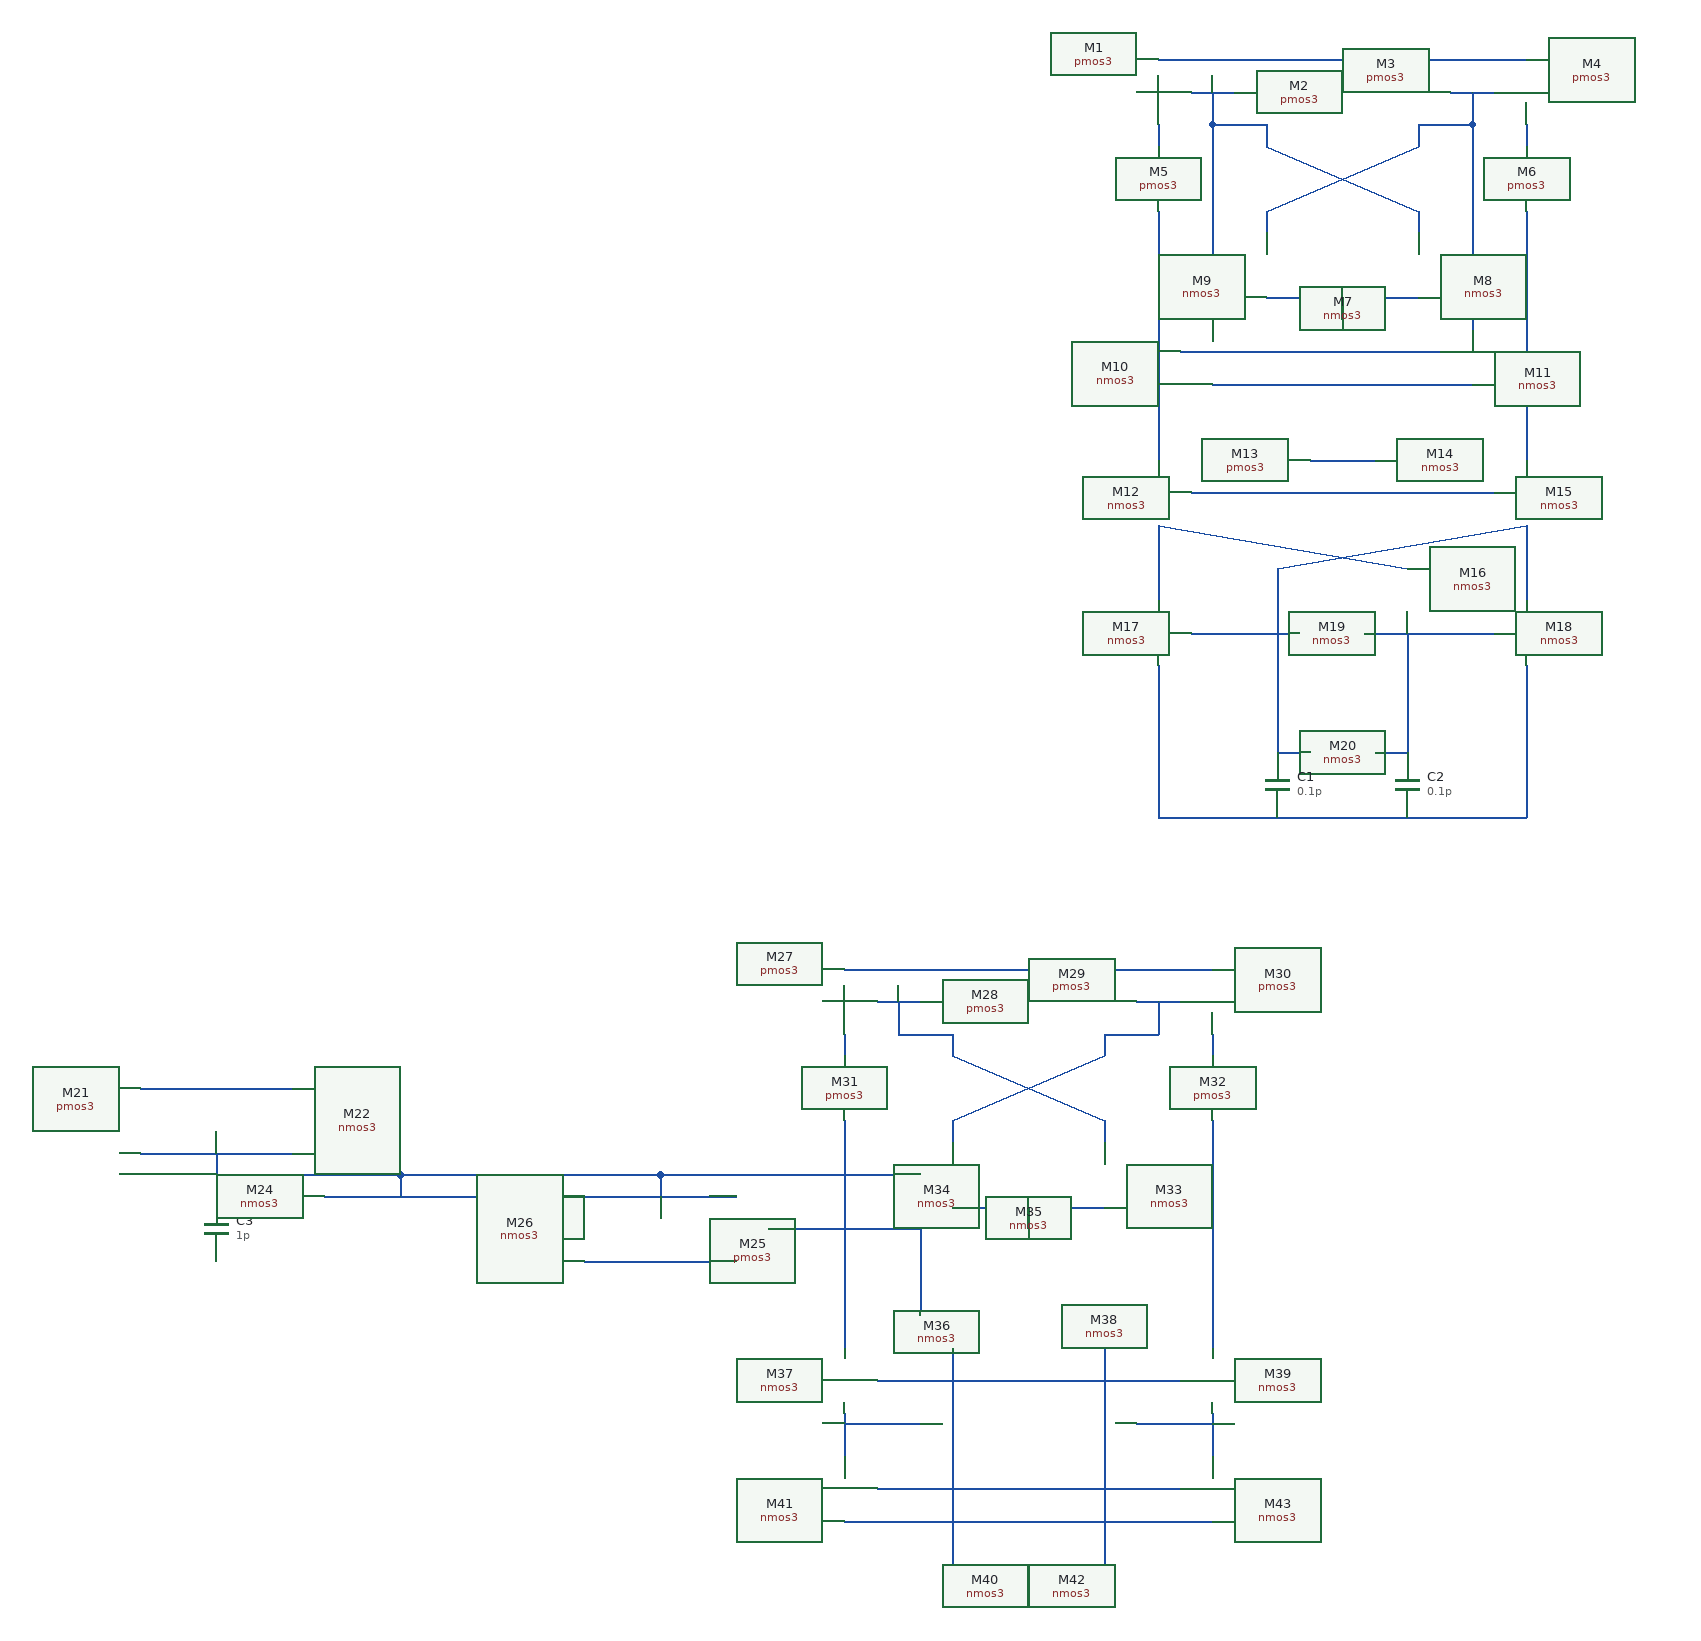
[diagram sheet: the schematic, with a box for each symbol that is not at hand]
v {xschem version=3.4.3 file_version=1.2
}
G {}
K {}
V {}
S {}
E {}
N -260 -400 80 -400 {
lab=#net1}
N -230 -370 -190 -370 {
lab=#net2}
N -210 -370 -210 -340 {
lab=#net2}
N -210 -340 -160 -340 {
lab=#net2}
N 10 -370 50 -370 {
lab=#net3}
N 30 -370 30 -340 {
lab=#net3}
N -20 -340 30 -340 {
lab=#net3}
N -160 -340 -160 -320 {
lab=#net2}
N -20 -260 -20 -240 {
lab=#net2}
N -20 -340 -20 -320 {
lab=#net3}
N -160 -260 -160 -240 {
lab=#net3}
N -160 -260 -20 -320 {
lab=#net3}
N -160 -320 -20 -260 {
lab=#net2}
N 80 -340 80 -320 {
lab=#net4}
N -260 -340 -260 -320 {
lab=#net5}
N -160 -180 -20 -180 {
lab=#net6}
N -90 -180 -90 -160 {
lab=#net6}
N -240 -130 0 -130 {
lab=#net7}
N -210 -100 30 -100 {
lab=#net8}
N -210 -340 -210 -160 {
lab=#net2}
N 30 -340 30 -150 {
lab=#net3}
N -260 -260 -260 -30 {
lab=#net9}
N -120 -30 -60 -30 {
lab=#net10}
N 80 -260 80 -30 {
lab=#net11}
N -230 -0 50 0 {
lab=#net12}
N -230 130 -130 130 {
lab=#net13}
N -70 130 50 130 {
lab=#net14}
N -260 30 -260 100 {
lab=#net15}
N 80 30 80 100 {
lab=#net13}
N -260 30 -30 70 {
lab=#net15}
N -150 70 80 30 {
lab=#net13}
N -150 70 -150 130 {
lab=#net13}
N -150 130 -150 240 {
lab=#net13}
N -150 240 -120 240 {
lab=#net13}
N -60 240 -30 240 {
lab=#net14}
N -30 130 -30 240 {
lab=#net14}
N -260 160 -260 300 {
lab=#net16}
N -260 300 80 300 {
lab=#net16}
N 80 160 80 300 {
lab=#net16}
N -1200 610 -1060 610 {
lab=#net17}
N -1200 550 -1060 550 {
lab=#net18}
N -1130 610 -1130 650 {
lab=#net17}
N -1130 630 -960 630 {
lab=#net17}
N -1030 650 -890 650 {
lab=#net17}
N -960 630 -960 650 {
lab=#net17}
N -790 650 -650 650 {
lab=#net17}
N -960 630 -720 630 {
lab=#net17}
N -720 630 -720 650 {
lab=#net17}
N -790 710 -650 710 {
lab=#net19}
N -550 440 -210 440 {
lab=#net20}
N -520 470 -480 470 {
lab=#net21}
N -500 470 -500 500 {
lab=#net21}
N -500 500 -450 500 {
lab=#net21}
N -280 470 -240 470 {
lab=#net22}
N -260 470 -260 500 {
lab=#net22}
N -310 500 -260 500 {
lab=#net22}
N -450 500 -450 520 {
lab=#net21}
N -310 580 -310 600 {
lab=#net21}
N -310 500 -310 520 {
lab=#net22}
N -450 580 -450 600 {
lab=#net22}
N -450 580 -310 520 {
lab=#net22}
N -450 520 -310 580 {
lab=#net21}
N -210 500 -210 520 {
lab=#net23}
N -550 500 -550 520 {
lab=#net24}
N -450 660 -310 660 {
lab=#net25}
N -380 660 -380 680 {
lab=#net25}
N -720 630 -480 630 {
lab=#net17}
N -550 580 -550 790 {
lab=#net26}
N -620 680 -480 680 {
lab=#net27}
N -480 680 -480 760 {
lab=#net27}
N -210 580 -210 790 {
lab=#net28}
N -520 820 -240 820 {
lab=#net29}
N -550 850 -550 890 {
lab=#net30}
N -550 860 -480 860 {
lab=#net30}
N -210 850 -210 890 {
lab=#net30}
N -280 860 -210 860 {
lab=#net30}
N -310 790 -310 990 {}
N -450 790 -450 990 {}
N -550 950 -210 950 {}
N -520 920 -240 920 {}
C {madvlsi/pmos3.sym} -260 -370 0 1 {name=M1
L=0.15
W=1
body=VDD
nf=1
mult=1
ad="'int((nf+1)/2) * W/nf * 0.29'" 
pd="'2*int((nf+1)/2) * (W/nf + 0.29)'"
as="'int((nf+2)/2) * W/nf * 0.29'" 
ps="'2*int((nf+2)/2) * (W/nf + 0.29)'"
nrd="'0.29 / W'" nrs="'0.29 / W'"
sa=0 sb=0 sd=0
model=pfet_01v8
spiceprefix=X
}
C {madvlsi/pmos3.sym} -160 -370 0 0 {name=M2
L=0.15
W=1
body=VDD
nf=1
mult=1
ad="'int((nf+1)/2) * W/nf * 0.29'" 
pd="'2*int((nf+1)/2) * (W/nf + 0.29)'"
as="'int((nf+2)/2) * W/nf * 0.29'" 
ps="'2*int((nf+2)/2) * (W/nf + 0.29)'"
nrd="'0.29 / W'" nrs="'0.29 / W'"
sa=0 sb=0 sd=0
model=pfet_01v8
spiceprefix=X
}
C {madvlsi/pmos3.sym} -20 -370 0 1 {name=M3
L=0.15
W=1
body=VDD
nf=1
mult=1
ad="'int((nf+1)/2) * W/nf * 0.29'" 
pd="'2*int((nf+1)/2) * (W/nf + 0.29)'"
as="'int((nf+2)/2) * W/nf * 0.29'" 
ps="'2*int((nf+2)/2) * (W/nf + 0.29)'"
nrd="'0.29 / W'" nrs="'0.29 / W'"
sa=0 sb=0 sd=0
model=pfet_01v8
spiceprefix=X
}
C {madvlsi/pmos3.sym} 80 -370 0 0 {name=M4
L=0.15
W=1
body=VDD
nf=1
mult=1
ad="'int((nf+1)/2) * W/nf * 0.29'" 
pd="'2*int((nf+1)/2) * (W/nf + 0.29)'"
as="'int((nf+2)/2) * W/nf * 0.29'" 
ps="'2*int((nf+2)/2) * (W/nf + 0.29)'"
nrd="'0.29 / W'" nrs="'0.29 / W'"
sa=0 sb=0 sd=0
model=pfet_01v8
spiceprefix=X
}
C {madvlsi/pmos3.sym} -260 -290 0 0 {name=M5
L=0.15
W=1
body=VDD
nf=1
mult=1
ad="'int((nf+1)/2) * W/nf * 0.29'" 
pd="'2*int((nf+1)/2) * (W/nf + 0.29)'"
as="'int((nf+2)/2) * W/nf * 0.29'" 
ps="'2*int((nf+2)/2) * (W/nf + 0.29)'"
nrd="'0.29 / W'" nrs="'0.29 / W'"
sa=0 sb=0 sd=0
model=pfet_01v8
spiceprefix=X
}
C {madvlsi/pmos3.sym} 80 -290 0 1 {name=M6
L=0.15
W=1
body=VDD
nf=1
mult=1
ad="'int((nf+1)/2) * W/nf * 0.29'" 
pd="'2*int((nf+1)/2) * (W/nf + 0.29)'"
as="'int((nf+2)/2) * W/nf * 0.29'" 
ps="'2*int((nf+2)/2) * (W/nf + 0.29)'"
nrd="'0.29 / W'" nrs="'0.29 / W'"
sa=0 sb=0 sd=0
model=pfet_01v8
spiceprefix=X
}
C {madvlsi/nmos3.sym} -90 -130 0 0 {name=M7
L=0.15
W=1
body=GND
nf=1
mult=1
ad="'int((nf+1)/2) * W/nf * 0.29'" 
pd="'2*int((nf+1)/2) * (W/nf + 0.29)'"
as="'int((nf+2)/2) * W/nf * 0.29'" 
ps="'2*int((nf+2)/2) * (W/nf + 0.29)'"
nrd="'0.29 / W'" nrs="'0.29 / W'"
sa=0 sb=0 sd=0
model=nfet_01v8
spiceprefix=X
}
C {madvlsi/nmos3.sym} -20 -210 0 1 {name=M8
L=0.15
W=1
body=GND
nf=1
mult=1
ad="'int((nf+1)/2) * W/nf * 0.29'" 
pd="'2*int((nf+1)/2) * (W/nf + 0.29)'"
as="'int((nf+2)/2) * W/nf * 0.29'" 
ps="'2*int((nf+2)/2) * (W/nf + 0.29)'"
nrd="'0.29 / W'" nrs="'0.29 / W'"
sa=0 sb=0 sd=0
model=nfet_01v8
spiceprefix=X
}
C {madvlsi/nmos3.sym} -160 -210 0 0 {name=M9
L=0.15
W=1
body=GND
nf=1
mult=1
ad="'int((nf+1)/2) * W/nf * 0.29'" 
pd="'2*int((nf+1)/2) * (W/nf + 0.29)'"
as="'int((nf+2)/2) * W/nf * 0.29'" 
ps="'2*int((nf+2)/2) * (W/nf + 0.29)'"
nrd="'0.29 / W'" nrs="'0.29 / W'"
sa=0 sb=0 sd=0
model=nfet_01v8
spiceprefix=X
}
C {madvlsi/nmos3.sym} -210 -130 0 0 {name=M10
L=0.15
W=1
body=GND
nf=1
mult=1
ad="'int((nf+1)/2) * W/nf * 0.29'" 
pd="'2*int((nf+1)/2) * (W/nf + 0.29)'"
as="'int((nf+2)/2) * W/nf * 0.29'" 
ps="'2*int((nf+2)/2) * (W/nf + 0.29)'"
nrd="'0.29 / W'" nrs="'0.29 / W'"
sa=0 sb=0 sd=0
model=nfet_01v8
spiceprefix=X
}
C {madvlsi/nmos3.sym} 30 -130 0 0 {name=M11
L=0.15
W=1
body=GND
nf=1
mult=1
ad="'int((nf+1)/2) * W/nf * 0.29'" 
pd="'2*int((nf+1)/2) * (W/nf + 0.29)'"
as="'int((nf+2)/2) * W/nf * 0.29'" 
ps="'2*int((nf+2)/2) * (W/nf + 0.29)'"
nrd="'0.29 / W'" nrs="'0.29 / W'"
sa=0 sb=0 sd=0
model=nfet_01v8
spiceprefix=X
}
C {madvlsi/nmos3.sym} -260 0 0 1 {name=M12
L=0.15
W=1
body=GND
nf=1
mult=1
ad="'int((nf+1)/2) * W/nf * 0.29'" 
pd="'2*int((nf+1)/2) * (W/nf + 0.29)'"
as="'int((nf+2)/2) * W/nf * 0.29'" 
ps="'2*int((nf+2)/2) * (W/nf + 0.29)'"
nrd="'0.29 / W'" nrs="'0.29 / W'"
sa=0 sb=0 sd=0
model=nfet_01v8
spiceprefix=X
}
C {madvlsi/pmos3.sym} -150 -30 0 1 {name=M13
L=0.15
W=1
body=VDD
nf=1
mult=1
ad="'int((nf+1)/2) * W/nf * 0.29'" 
pd="'2*int((nf+1)/2) * (W/nf + 0.29)'"
as="'int((nf+2)/2) * W/nf * 0.29'" 
ps="'2*int((nf+2)/2) * (W/nf + 0.29)'"
nrd="'0.29 / W'" nrs="'0.29 / W'"
sa=0 sb=0 sd=0
model=pfet_01v8
spiceprefix=X
}
C {madvlsi/nmos3.sym} -30 -30 0 0 {name=M14
L=0.15
W=1
body=GND
nf=1
mult=1
ad="'int((nf+1)/2) * W/nf * 0.29'" 
pd="'2*int((nf+1)/2) * (W/nf + 0.29)'"
as="'int((nf+2)/2) * W/nf * 0.29'" 
ps="'2*int((nf+2)/2) * (W/nf + 0.29)'"
nrd="'0.29 / W'" nrs="'0.29 / W'"
sa=0 sb=0 sd=0
model=nfet_01v8
spiceprefix=X
}
C {madvlsi/nmos3.sym} 80 0 0 0 {name=M15
L=0.15
W=1
body=GND
nf=1
mult=1
ad="'int((nf+1)/2) * W/nf * 0.29'" 
pd="'2*int((nf+1)/2) * (W/nf + 0.29)'"
as="'int((nf+2)/2) * W/nf * 0.29'" 
ps="'2*int((nf+2)/2) * (W/nf + 0.29)'"
nrd="'0.29 / W'" nrs="'0.29 / W'"
sa=0 sb=0 sd=0
model=nfet_01v8
spiceprefix=X
}
C {madvlsi/nmos3.sym} -30 100 0 0 {name=M16
L=0.15
W=1
body=GND
nf=1
mult=1
ad="'int((nf+1)/2) * W/nf * 0.29'" 
pd="'2*int((nf+1)/2) * (W/nf + 0.29)'"
as="'int((nf+2)/2) * W/nf * 0.29'" 
ps="'2*int((nf+2)/2) * (W/nf + 0.29)'"
nrd="'0.29 / W'" nrs="'0.29 / W'"
sa=0 sb=0 sd=0
model=nfet_01v8
spiceprefix=X
}
C {madvlsi/nmos3.sym} -260 130 0 1 {name=M17
L=0.15
W=1
body=GND
nf=1
mult=1
ad="'int((nf+1)/2) * W/nf * 0.29'" 
pd="'2*int((nf+1)/2) * (W/nf + 0.29)'"
as="'int((nf+2)/2) * W/nf * 0.29'" 
ps="'2*int((nf+2)/2) * (W/nf + 0.29)'"
nrd="'0.29 / W'" nrs="'0.29 / W'"
sa=0 sb=0 sd=0
model=nfet_01v8
spiceprefix=X
}
C {madvlsi/nmos3.sym} 80 130 0 0 {name=M18
L=0.15
W=1
body=GND
nf=1
mult=1
ad="'int((nf+1)/2) * W/nf * 0.29'" 
pd="'2*int((nf+1)/2) * (W/nf + 0.29)'"
as="'int((nf+2)/2) * W/nf * 0.29'" 
ps="'2*int((nf+2)/2) * (W/nf + 0.29)'"
nrd="'0.29 / W'" nrs="'0.29 / W'"
sa=0 sb=0 sd=0
model=nfet_01v8
spiceprefix=X
}
C {madvlsi/nmos3.sym} -100 130 3 0 {name=M19
L=0.15
W=1
body=GND
nf=1
mult=1
ad="'int((nf+1)/2) * W/nf * 0.29'" 
pd="'2*int((nf+1)/2) * (W/nf + 0.29)'"
as="'int((nf+2)/2) * W/nf * 0.29'" 
ps="'2*int((nf+2)/2) * (W/nf + 0.29)'"
nrd="'0.29 / W'" nrs="'0.29 / W'"
sa=0 sb=0 sd=0
model=nfet_01v8
spiceprefix=X
}
C {madvlsi/nmos3.sym} -90 240 3 0 {name=M20
L=0.15
W=1
body=GND
nf=1
mult=1
ad="'int((nf+1)/2) * W/nf * 0.29'" 
pd="'2*int((nf+1)/2) * (W/nf + 0.29)'"
as="'int((nf+2)/2) * W/nf * 0.29'" 
ps="'2*int((nf+2)/2) * (W/nf + 0.29)'"
nrd="'0.29 / W'" nrs="'0.29 / W'"
sa=0 sb=0 sd=0
model=nfet_01v8
spiceprefix=X
}
C {madvlsi/capacitor.sym} -150 270 0 0 {name=C1
value=0.1p
m=1}
C {madvlsi/capacitor.sym} -30 270 0 0 {name=C2
value=0.1p
m=1}
C {madvlsi/pmos3.sym} -1200 580 0 0 {name=M21
L=0.15
W=1
body=VDD
nf=1
mult=1
ad="'int((nf+1)/2) * W/nf * 0.29'" 
pd="'2*int((nf+1)/2) * (W/nf + 0.29)'"
as="'int((nf+2)/2) * W/nf * 0.29'" 
ps="'2*int((nf+2)/2) * (W/nf + 0.29)'"
nrd="'0.29 / W'" nrs="'0.29 / W'"
sa=0 sb=0 sd=0
model=pfet_01v8
spiceprefix=X
}
C {madvlsi/nmos3.sym} -1060 580 2 0 {name=M22
L=0.15
W=1
body=GND
nf=1
mult=1
ad="'int((nf+1)/2) * W/nf * 0.29'" 
pd="'2*int((nf+1)/2) * (W/nf + 0.29)'"
as="'int((nf+2)/2) * W/nf * 0.29'" 
ps="'2*int((nf+2)/2) * (W/nf + 0.29)'"
nrd="'0.29 / W'" nrs="'0.29 / W'"
sa=0 sb=0 sd=0
model=nfet_01v8
spiceprefix=X
}
C {madvlsi/capacitor.sym} -1130 680 0 0 {name=C3
value=1p
m=1}
C {madvlsi/pmos3.sym} -890 680 0 1 {name=M23
L=0.15
W=1
body=VDD
nf=1
mult=1
ad="'int((nf+1)/2) * W/nf * 0.29'" 
pd="'2*int((nf+1)/2) * (W/nf + 0.29)'"
as="'int((nf+2)/2) * W/nf * 0.29'" 
ps="'2*int((nf+2)/2) * (W/nf + 0.29)'"
nrd="'0.29 / W'" nrs="'0.29 / W'"
sa=0 sb=0 sd=0
model=pfet_01v8
spiceprefix=X
}
C {madvlsi/nmos3.sym} -1030 680 2 1 {name=M24
L=0.15
W=1
body=GND
nf=1
mult=1
ad="'int((nf+1)/2) * W/nf * 0.29'" 
pd="'2*int((nf+1)/2) * (W/nf + 0.29)'"
as="'int((nf+2)/2) * W/nf * 0.29'" 
ps="'2*int((nf+2)/2) * (W/nf + 0.29)'"
nrd="'0.29 / W'" nrs="'0.29 / W'"
sa=0 sb=0 sd=0
model=nfet_01v8
spiceprefix=X
}
C {madvlsi/pmos3.sym} -650 680 0 1 {name=M25
L=0.15
W=1
body=VDD
nf=1
mult=1
ad="'int((nf+1)/2) * W/nf * 0.29'" 
pd="'2*int((nf+1)/2) * (W/nf + 0.29)'"
as="'int((nf+2)/2) * W/nf * 0.29'" 
ps="'2*int((nf+2)/2) * (W/nf + 0.29)'"
nrd="'0.29 / W'" nrs="'0.29 / W'"
sa=0 sb=0 sd=0
model=pfet_01v8
spiceprefix=X
}
C {madvlsi/nmos3.sym} -790 680 2 1 {name=M26
L=0.15
W=1
body=GND
nf=1
mult=1
ad="'int((nf+1)/2) * W/nf * 0.29'" 
pd="'2*int((nf+1)/2) * (W/nf + 0.29)'"
as="'int((nf+2)/2) * W/nf * 0.29'" 
ps="'2*int((nf+2)/2) * (W/nf + 0.29)'"
nrd="'0.29 / W'" nrs="'0.29 / W'"
sa=0 sb=0 sd=0
model=nfet_01v8
spiceprefix=X
}
C {madvlsi/pmos3.sym} -550 470 0 1 {name=M27
L=0.15
W=1
body=VDD
nf=1
mult=1
ad="'int((nf+1)/2) * W/nf * 0.29'" 
pd="'2*int((nf+1)/2) * (W/nf + 0.29)'"
as="'int((nf+2)/2) * W/nf * 0.29'" 
ps="'2*int((nf+2)/2) * (W/nf + 0.29)'"
nrd="'0.29 / W'" nrs="'0.29 / W'"
sa=0 sb=0 sd=0
model=pfet_01v8
spiceprefix=X
}
C {madvlsi/pmos3.sym} -450 470 0 0 {name=M28
L=0.15
W=1
body=VDD
nf=1
mult=1
ad="'int((nf+1)/2) * W/nf * 0.29'" 
pd="'2*int((nf+1)/2) * (W/nf + 0.29)'"
as="'int((nf+2)/2) * W/nf * 0.29'" 
ps="'2*int((nf+2)/2) * (W/nf + 0.29)'"
nrd="'0.29 / W'" nrs="'0.29 / W'"
sa=0 sb=0 sd=0
model=pfet_01v8
spiceprefix=X
}
C {madvlsi/pmos3.sym} -310 470 0 1 {name=M29
L=0.15
W=1
body=VDD
nf=1
mult=1
ad="'int((nf+1)/2) * W/nf * 0.29'" 
pd="'2*int((nf+1)/2) * (W/nf + 0.29)'"
as="'int((nf+2)/2) * W/nf * 0.29'" 
ps="'2*int((nf+2)/2) * (W/nf + 0.29)'"
nrd="'0.29 / W'" nrs="'0.29 / W'"
sa=0 sb=0 sd=0
model=pfet_01v8
spiceprefix=X
}
C {madvlsi/pmos3.sym} -210 470 0 0 {name=M30
L=0.15
W=1
body=VDD
nf=1
mult=1
ad="'int((nf+1)/2) * W/nf * 0.29'" 
pd="'2*int((nf+1)/2) * (W/nf + 0.29)'"
as="'int((nf+2)/2) * W/nf * 0.29'" 
ps="'2*int((nf+2)/2) * (W/nf + 0.29)'"
nrd="'0.29 / W'" nrs="'0.29 / W'"
sa=0 sb=0 sd=0
model=pfet_01v8
spiceprefix=X
}
C {madvlsi/pmos3.sym} -550 550 0 0 {name=M31
L=0.15
W=1
body=VDD
nf=1
mult=1
ad="'int((nf+1)/2) * W/nf * 0.29'" 
pd="'2*int((nf+1)/2) * (W/nf + 0.29)'"
as="'int((nf+2)/2) * W/nf * 0.29'" 
ps="'2*int((nf+2)/2) * (W/nf + 0.29)'"
nrd="'0.29 / W'" nrs="'0.29 / W'"
sa=0 sb=0 sd=0
model=pfet_01v8
spiceprefix=X
}
C {madvlsi/pmos3.sym} -210 550 0 1 {name=M32
L=0.15
W=1
body=VDD
nf=1
mult=1
ad="'int((nf+1)/2) * W/nf * 0.29'" 
pd="'2*int((nf+1)/2) * (W/nf + 0.29)'"
as="'int((nf+2)/2) * W/nf * 0.29'" 
ps="'2*int((nf+2)/2) * (W/nf + 0.29)'"
nrd="'0.29 / W'" nrs="'0.29 / W'"
sa=0 sb=0 sd=0
model=pfet_01v8
spiceprefix=X
}
C {madvlsi/nmos3.sym} -310 630 0 1 {name=M33
L=0.15
W=1
body=GND
nf=1
mult=1
ad="'int((nf+1)/2) * W/nf * 0.29'" 
pd="'2*int((nf+1)/2) * (W/nf + 0.29)'"
as="'int((nf+2)/2) * W/nf * 0.29'" 
ps="'2*int((nf+2)/2) * (W/nf + 0.29)'"
nrd="'0.29 / W'" nrs="'0.29 / W'"
sa=0 sb=0 sd=0
model=nfet_01v8
spiceprefix=X
}
C {madvlsi/nmos3.sym} -450 630 0 0 {name=M34
L=0.15
W=1
body=GND
nf=1
mult=1
ad="'int((nf+1)/2) * W/nf * 0.29'" 
pd="'2*int((nf+1)/2) * (W/nf + 0.29)'"
as="'int((nf+2)/2) * W/nf * 0.29'" 
ps="'2*int((nf+2)/2) * (W/nf + 0.29)'"
nrd="'0.29 / W'" nrs="'0.29 / W'"
sa=0 sb=0 sd=0
model=nfet_01v8
spiceprefix=X
}
C {madvlsi/nmos3.sym} -380 710 0 0 {name=M35
L=0.15
W=1
body=GND
nf=1
mult=1
ad="'int((nf+1)/2) * W/nf * 0.29'" 
pd="'2*int((nf+1)/2) * (W/nf + 0.29)'"
as="'int((nf+2)/2) * W/nf * 0.29'" 
ps="'2*int((nf+2)/2) * (W/nf + 0.29)'"
nrd="'0.29 / W'" nrs="'0.29 / W'"
sa=0 sb=0 sd=0
model=nfet_01v8
spiceprefix=X
}
C {madvlsi/nmos3.sym} -480 790 0 1 {name=M36
L=0.15
W=1
body=GND
nf=1
mult=1
ad="'int((nf+1)/2) * W/nf * 0.29'" 
pd="'2*int((nf+1)/2) * (W/nf + 0.29)'"
as="'int((nf+2)/2) * W/nf * 0.29'" 
ps="'2*int((nf+2)/2) * (W/nf + 0.29)'"
nrd="'0.29 / W'" nrs="'0.29 / W'"
sa=0 sb=0 sd=0
model=nfet_01v8
spiceprefix=X
}
C {madvlsi/nmos3.sym} -550 820 0 1 {name=M37
L=0.15
W=1
body=GND
nf=1
mult=1
ad="'int((nf+1)/2) * W/nf * 0.29'" 
pd="'2*int((nf+1)/2) * (W/nf + 0.29)'"
as="'int((nf+2)/2) * W/nf * 0.29'" 
ps="'2*int((nf+2)/2) * (W/nf + 0.29)'"
nrd="'0.29 / W'" nrs="'0.29 / W'"
sa=0 sb=0 sd=0
model=nfet_01v8
spiceprefix=X
}
C {madvlsi/nmos3.sym} -280 790 0 0 {name=M38
L=0.15
W=1
body=GND
nf=1
mult=1
ad="'int((nf+1)/2) * W/nf * 0.29'" 
pd="'2*int((nf+1)/2) * (W/nf + 0.29)'"
as="'int((nf+2)/2) * W/nf * 0.29'" 
ps="'2*int((nf+2)/2) * (W/nf + 0.29)'"
nrd="'0.29 / W'" nrs="'0.29 / W'"
sa=0 sb=0 sd=0
model=nfet_01v8
spiceprefix=X
}
C {madvlsi/nmos3.sym} -210 820 0 0 {name=M39
L=0.15
W=1
body=GND
nf=1
mult=1
ad="'int((nf+1)/2) * W/nf * 0.29'" 
pd="'2*int((nf+1)/2) * (W/nf + 0.29)'"
as="'int((nf+2)/2) * W/nf * 0.29'" 
ps="'2*int((nf+2)/2) * (W/nf + 0.29)'"
nrd="'0.29 / W'" nrs="'0.29 / W'"
sa=0 sb=0 sd=0
model=nfet_01v8
spiceprefix=X
}
C {madvlsi/nmos3.sym} -480 890 0 1 {name=M40
L=0.15
W=1
body=GND
nf=1
mult=1
ad="'int((nf+1)/2) * W/nf * 0.29'" 
pd="'2*int((nf+1)/2) * (W/nf + 0.29)'"
as="'int((nf+2)/2) * W/nf * 0.29'" 
ps="'2*int((nf+2)/2) * (W/nf + 0.29)'"
nrd="'0.29 / W'" nrs="'0.29 / W'"
sa=0 sb=0 sd=0
model=nfet_01v8
spiceprefix=X
}
C {madvlsi/nmos3.sym} -550 920 0 1 {name=M41
L=0.15
W=1
body=GND
nf=1
mult=1
ad="'int((nf+1)/2) * W/nf * 0.29'" 
pd="'2*int((nf+1)/2) * (W/nf + 0.29)'"
as="'int((nf+2)/2) * W/nf * 0.29'" 
ps="'2*int((nf+2)/2) * (W/nf + 0.29)'"
nrd="'0.29 / W'" nrs="'0.29 / W'"
sa=0 sb=0 sd=0
model=nfet_01v8
spiceprefix=X
}
C {madvlsi/nmos3.sym} -280 890 0 0 {name=M42
L=0.15
W=1
body=GND
nf=1
mult=1
ad="'int((nf+1)/2) * W/nf * 0.29'" 
pd="'2*int((nf+1)/2) * (W/nf + 0.29)'"
as="'int((nf+2)/2) * W/nf * 0.29'" 
ps="'2*int((nf+2)/2) * (W/nf + 0.29)'"
nrd="'0.29 / W'" nrs="'0.29 / W'"
sa=0 sb=0 sd=0
model=nfet_01v8
spiceprefix=X
}
C {madvlsi/nmos3.sym} -210 920 0 0 {name=M43
L=0.15
W=1
body=GND
nf=1
mult=1
ad="'int((nf+1)/2) * W/nf * 0.29'" 
pd="'2*int((nf+1)/2) * (W/nf + 0.29)'"
as="'int((nf+2)/2) * W/nf * 0.29'" 
ps="'2*int((nf+2)/2) * (W/nf + 0.29)'"
nrd="'0.29 / W'" nrs="'0.29 / W'"
sa=0 sb=0 sd=0
model=nfet_01v8
spiceprefix=X
}
